VERSION 5.7 ;
  NOWIREEXTENSIONATPIN ON ;
  DIVIDERCHAR "/" ;
  BUSBITCHARS "[]" ;
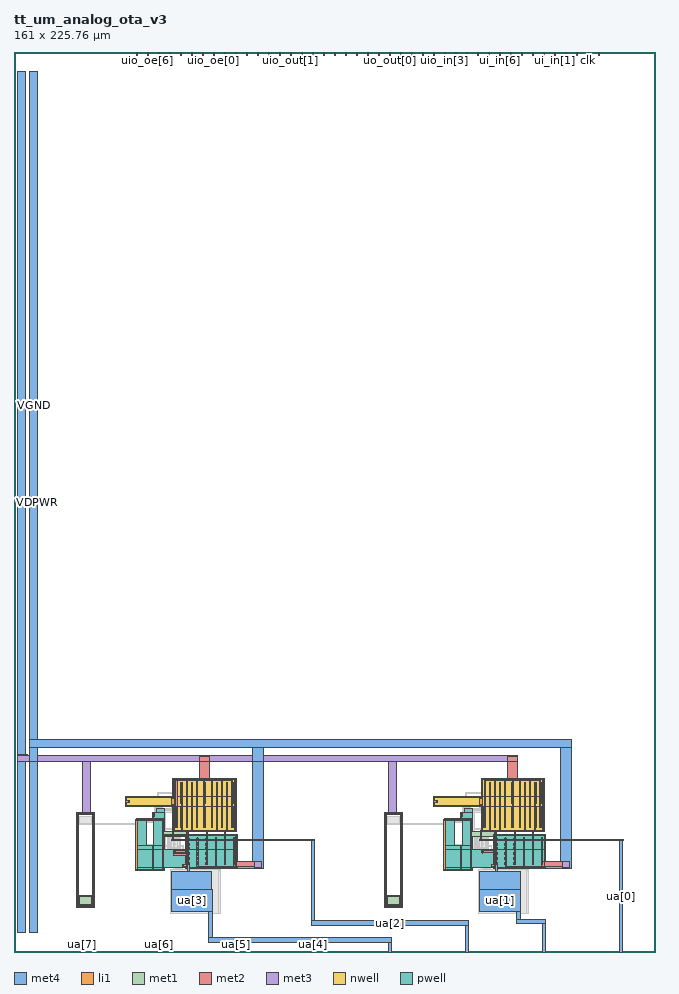
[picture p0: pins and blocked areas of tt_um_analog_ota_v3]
MACRO tt_um_analog_ota_v3
  CLASS BLOCK ;
  FOREIGN tt_um_analog_ota_v3 ;
  ORIGIN 0.000 0.000 ;
  SIZE 161.000 BY 225.760 ;
  PIN clk
    PORT
      LAYER met4 ;
        RECT 143.830 224.760 144.130 225.760 ;
    END
  END clk
  PIN ena
    PORT
      LAYER met4 ;
        RECT 146.590 224.760 146.890 225.760 ;
    END
  END ena
  PIN rst_n
    PORT
      LAYER met4 ;
        RECT 141.070 224.760 141.370 225.760 ;
    END
  END rst_n
  PIN ua[0]
    ANTENNAGATEAREA 0.625000 ;
    PORT
      LAYER li1 ;
        RECT 117.640 28.055 118.140 28.225 ;
      LAYER met1 ;
        RECT 117.715 28.255 118.075 28.270 ;
        RECT 117.660 28.025 118.120 28.255 ;
        RECT 117.715 28.010 118.075 28.025 ;
      LAYER met2 ;
        RECT 117.765 27.950 118.045 28.330 ;
      LAYER met3 ;
        RECT 117.715 27.975 152.770 28.305 ;
        RECT 151.760 27.970 152.770 27.975 ;
      LAYER met4 ;
        RECT 151.805 27.965 152.725 28.310 ;
        RECT 151.810 0.000 152.710 27.965 ;
    END
  END ua[0]
  PIN ua[1]
    ANTENNAGATEAREA 0.625000 ;
    ANTENNADIFFAREA 15.688999 ;
    PORT
      LAYER li1 ;
        RECT 119.250 37.155 119.420 42.495 ;
        RECT 121.830 37.155 122.000 42.495 ;
        RECT 128.110 37.155 128.280 42.495 ;
        RECT 130.690 37.155 130.860 42.495 ;
        RECT 119.250 31.215 119.420 36.555 ;
        RECT 121.830 31.215 122.000 36.555 ;
        RECT 128.110 31.215 128.280 36.555 ;
        RECT 130.690 31.215 130.860 36.555 ;
        RECT 116.850 28.055 117.350 28.225 ;
        RECT 120.935 27.925 121.105 28.615 ;
        RECT 125.515 27.925 125.685 28.615 ;
        RECT 130.095 27.925 130.265 28.615 ;
        RECT 120.935 26.725 121.105 27.415 ;
        RECT 125.515 26.725 125.685 27.415 ;
        RECT 130.095 26.725 130.265 27.415 ;
        RECT 120.935 25.525 121.105 26.215 ;
        RECT 125.515 25.525 125.685 26.215 ;
        RECT 130.095 25.525 130.265 26.215 ;
        RECT 120.935 24.325 121.105 25.015 ;
        RECT 125.515 24.325 125.685 25.015 ;
        RECT 130.095 24.325 130.265 25.015 ;
        RECT 120.935 23.125 121.105 23.815 ;
        RECT 125.515 23.125 125.685 23.815 ;
        RECT 130.095 23.125 130.265 23.815 ;
        RECT 120.935 21.925 121.105 22.615 ;
        RECT 125.515 21.925 125.685 22.615 ;
        RECT 130.095 21.925 130.265 22.615 ;
      LAYER met1 ;
        RECT 119.220 42.460 119.450 42.475 ;
        RECT 121.800 42.460 122.030 42.475 ;
        RECT 128.080 42.460 128.310 42.475 ;
        RECT 130.660 42.460 130.890 42.475 ;
        RECT 119.155 37.190 119.515 42.460 ;
        RECT 121.735 37.190 122.095 42.460 ;
        RECT 128.015 37.190 128.375 42.460 ;
        RECT 130.595 37.190 130.955 42.460 ;
        RECT 119.220 37.175 119.450 37.190 ;
        RECT 121.800 37.175 122.030 37.190 ;
        RECT 128.080 37.175 128.310 37.190 ;
        RECT 130.660 37.175 130.890 37.190 ;
        RECT 119.220 36.520 119.450 36.535 ;
        RECT 121.800 36.520 122.030 36.535 ;
        RECT 128.080 36.520 128.310 36.535 ;
        RECT 130.660 36.520 130.890 36.535 ;
        RECT 119.155 31.250 119.515 36.520 ;
        RECT 121.735 31.250 122.095 36.520 ;
        RECT 128.015 31.250 128.375 36.520 ;
        RECT 130.595 31.250 130.955 36.520 ;
        RECT 119.220 31.235 119.450 31.250 ;
        RECT 121.800 31.235 122.030 31.250 ;
        RECT 128.080 31.235 128.310 31.250 ;
        RECT 130.660 31.235 130.890 31.250 ;
        RECT 120.905 28.535 121.135 28.595 ;
        RECT 125.485 28.535 125.715 28.595 ;
        RECT 130.065 28.535 130.295 28.595 ;
        RECT 116.915 28.255 117.275 28.270 ;
        RECT 116.870 28.025 117.330 28.255 ;
        RECT 116.915 28.010 117.275 28.025 ;
        RECT 120.840 28.005 121.200 28.535 ;
        RECT 125.420 28.005 125.780 28.535 ;
        RECT 130.000 28.005 130.360 28.535 ;
        RECT 120.905 27.945 121.135 28.005 ;
        RECT 125.485 27.945 125.715 28.005 ;
        RECT 130.065 27.945 130.295 28.005 ;
        RECT 120.905 27.335 121.135 27.395 ;
        RECT 125.485 27.335 125.715 27.395 ;
        RECT 130.065 27.335 130.295 27.395 ;
        RECT 120.840 26.805 121.200 27.335 ;
        RECT 125.420 26.805 125.780 27.335 ;
        RECT 130.000 26.805 130.360 27.335 ;
        RECT 120.905 26.745 121.135 26.805 ;
        RECT 125.485 26.745 125.715 26.805 ;
        RECT 130.065 26.745 130.295 26.805 ;
        RECT 120.905 26.135 121.135 26.195 ;
        RECT 125.485 26.135 125.715 26.195 ;
        RECT 130.065 26.135 130.295 26.195 ;
        RECT 120.840 25.605 121.200 26.135 ;
        RECT 125.420 25.605 125.780 26.135 ;
        RECT 130.000 25.605 130.360 26.135 ;
        RECT 120.905 25.545 121.135 25.605 ;
        RECT 125.485 25.545 125.715 25.605 ;
        RECT 130.065 25.545 130.295 25.605 ;
        RECT 120.905 24.935 121.135 24.995 ;
        RECT 125.485 24.935 125.715 24.995 ;
        RECT 130.065 24.935 130.295 24.995 ;
        RECT 120.840 24.405 121.200 24.935 ;
        RECT 125.420 24.405 125.780 24.935 ;
        RECT 130.000 24.405 130.360 24.935 ;
        RECT 120.905 24.345 121.135 24.405 ;
        RECT 125.485 24.345 125.715 24.405 ;
        RECT 130.065 24.345 130.295 24.405 ;
        RECT 120.905 23.735 121.135 23.795 ;
        RECT 125.485 23.735 125.715 23.795 ;
        RECT 130.065 23.735 130.295 23.795 ;
        RECT 120.840 23.205 121.200 23.735 ;
        RECT 125.420 23.205 125.780 23.735 ;
        RECT 130.000 23.205 130.360 23.735 ;
        RECT 120.905 23.145 121.135 23.205 ;
        RECT 125.485 23.145 125.715 23.205 ;
        RECT 130.065 23.145 130.295 23.205 ;
        RECT 120.905 22.535 121.135 22.595 ;
        RECT 125.485 22.535 125.715 22.595 ;
        RECT 130.065 22.535 130.295 22.595 ;
        RECT 120.840 22.005 121.200 22.535 ;
        RECT 125.420 22.005 125.780 22.535 ;
        RECT 130.000 22.005 130.360 22.535 ;
        RECT 120.905 21.945 121.135 22.005 ;
        RECT 125.485 21.945 125.715 22.005 ;
        RECT 130.065 21.945 130.295 22.005 ;
      LAYER met2 ;
        RECT 119.205 30.450 119.465 42.510 ;
        RECT 121.785 30.450 122.045 42.510 ;
        RECT 128.065 30.450 128.325 42.510 ;
        RECT 130.645 30.450 130.905 42.510 ;
        RECT 116.965 30.190 130.905 30.450 ;
        RECT 116.965 28.320 117.185 30.190 ;
        RECT 116.965 27.960 117.225 28.320 ;
        RECT 120.890 22.460 121.150 30.190 ;
        RECT 120.880 22.080 121.160 22.460 ;
        RECT 120.890 21.955 121.150 22.080 ;
        RECT 125.470 21.955 125.730 30.190 ;
        RECT 130.050 21.955 130.310 30.190 ;
      LAYER met3 ;
        RECT 120.770 22.020 121.270 22.520 ;
      LAYER met4 ;
        RECT 120.855 22.105 121.185 22.435 ;
        RECT 120.860 20.175 121.180 22.105 ;
        RECT 116.835 15.780 126.945 20.175 ;
        RECT 116.835 10.065 127.015 15.780 ;
        RECT 126.115 8.255 127.015 10.065 ;
        RECT 126.115 7.030 133.390 8.255 ;
        RECT 132.490 0.000 133.390 7.030 ;
    END
  END ua[1]
  PIN ua[2]
    ANTENNAGATEAREA 0.625000 ;
    PORT
      LAYER li1 ;
        RECT 40.360 28.055 40.860 28.225 ;
      LAYER met1 ;
        RECT 40.435 28.255 40.795 28.270 ;
        RECT 40.380 28.025 40.840 28.255 ;
        RECT 40.435 28.010 40.795 28.025 ;
      LAYER met2 ;
        RECT 40.485 27.950 40.765 28.330 ;
      LAYER met3 ;
        RECT 40.435 27.975 75.490 28.305 ;
        RECT 74.480 27.970 75.490 27.975 ;
      LAYER met4 ;
        RECT 74.525 27.965 75.445 28.310 ;
        RECT 74.530 7.815 75.430 27.965 ;
        RECT 74.530 6.695 114.070 7.815 ;
        RECT 113.170 0.000 114.070 6.695 ;
    END
  END ua[2]
  PIN ua[3]
    ANTENNAGATEAREA 0.625000 ;
    ANTENNADIFFAREA 15.688999 ;
    PORT
      LAYER li1 ;
        RECT 41.970 37.155 42.140 42.495 ;
        RECT 44.550 37.155 44.720 42.495 ;
        RECT 50.830 37.155 51.000 42.495 ;
        RECT 53.410 37.155 53.580 42.495 ;
        RECT 41.970 31.215 42.140 36.555 ;
        RECT 44.550 31.215 44.720 36.555 ;
        RECT 50.830 31.215 51.000 36.555 ;
        RECT 53.410 31.215 53.580 36.555 ;
        RECT 39.570 28.055 40.070 28.225 ;
        RECT 43.655 27.925 43.825 28.615 ;
        RECT 48.235 27.925 48.405 28.615 ;
        RECT 52.815 27.925 52.985 28.615 ;
        RECT 43.655 26.725 43.825 27.415 ;
        RECT 48.235 26.725 48.405 27.415 ;
        RECT 52.815 26.725 52.985 27.415 ;
        RECT 43.655 25.525 43.825 26.215 ;
        RECT 48.235 25.525 48.405 26.215 ;
        RECT 52.815 25.525 52.985 26.215 ;
        RECT 43.655 24.325 43.825 25.015 ;
        RECT 48.235 24.325 48.405 25.015 ;
        RECT 52.815 24.325 52.985 25.015 ;
        RECT 43.655 23.125 43.825 23.815 ;
        RECT 48.235 23.125 48.405 23.815 ;
        RECT 52.815 23.125 52.985 23.815 ;
        RECT 43.655 21.925 43.825 22.615 ;
        RECT 48.235 21.925 48.405 22.615 ;
        RECT 52.815 21.925 52.985 22.615 ;
      LAYER met1 ;
        RECT 41.940 42.460 42.170 42.475 ;
        RECT 44.520 42.460 44.750 42.475 ;
        RECT 50.800 42.460 51.030 42.475 ;
        RECT 53.380 42.460 53.610 42.475 ;
        RECT 41.875 37.190 42.235 42.460 ;
        RECT 44.455 37.190 44.815 42.460 ;
        RECT 50.735 37.190 51.095 42.460 ;
        RECT 53.315 37.190 53.675 42.460 ;
        RECT 41.940 37.175 42.170 37.190 ;
        RECT 44.520 37.175 44.750 37.190 ;
        RECT 50.800 37.175 51.030 37.190 ;
        RECT 53.380 37.175 53.610 37.190 ;
        RECT 41.940 36.520 42.170 36.535 ;
        RECT 44.520 36.520 44.750 36.535 ;
        RECT 50.800 36.520 51.030 36.535 ;
        RECT 53.380 36.520 53.610 36.535 ;
        RECT 41.875 31.250 42.235 36.520 ;
        RECT 44.455 31.250 44.815 36.520 ;
        RECT 50.735 31.250 51.095 36.520 ;
        RECT 53.315 31.250 53.675 36.520 ;
        RECT 41.940 31.235 42.170 31.250 ;
        RECT 44.520 31.235 44.750 31.250 ;
        RECT 50.800 31.235 51.030 31.250 ;
        RECT 53.380 31.235 53.610 31.250 ;
        RECT 43.625 28.535 43.855 28.595 ;
        RECT 48.205 28.535 48.435 28.595 ;
        RECT 52.785 28.535 53.015 28.595 ;
        RECT 39.635 28.255 39.995 28.270 ;
        RECT 39.590 28.025 40.050 28.255 ;
        RECT 39.635 28.010 39.995 28.025 ;
        RECT 43.560 28.005 43.920 28.535 ;
        RECT 48.140 28.005 48.500 28.535 ;
        RECT 52.720 28.005 53.080 28.535 ;
        RECT 43.625 27.945 43.855 28.005 ;
        RECT 48.205 27.945 48.435 28.005 ;
        RECT 52.785 27.945 53.015 28.005 ;
        RECT 43.625 27.335 43.855 27.395 ;
        RECT 48.205 27.335 48.435 27.395 ;
        RECT 52.785 27.335 53.015 27.395 ;
        RECT 43.560 26.805 43.920 27.335 ;
        RECT 48.140 26.805 48.500 27.335 ;
        RECT 52.720 26.805 53.080 27.335 ;
        RECT 43.625 26.745 43.855 26.805 ;
        RECT 48.205 26.745 48.435 26.805 ;
        RECT 52.785 26.745 53.015 26.805 ;
        RECT 43.625 26.135 43.855 26.195 ;
        RECT 48.205 26.135 48.435 26.195 ;
        RECT 52.785 26.135 53.015 26.195 ;
        RECT 43.560 25.605 43.920 26.135 ;
        RECT 48.140 25.605 48.500 26.135 ;
        RECT 52.720 25.605 53.080 26.135 ;
        RECT 43.625 25.545 43.855 25.605 ;
        RECT 48.205 25.545 48.435 25.605 ;
        RECT 52.785 25.545 53.015 25.605 ;
        RECT 43.625 24.935 43.855 24.995 ;
        RECT 48.205 24.935 48.435 24.995 ;
        RECT 52.785 24.935 53.015 24.995 ;
        RECT 43.560 24.405 43.920 24.935 ;
        RECT 48.140 24.405 48.500 24.935 ;
        RECT 52.720 24.405 53.080 24.935 ;
        RECT 43.625 24.345 43.855 24.405 ;
        RECT 48.205 24.345 48.435 24.405 ;
        RECT 52.785 24.345 53.015 24.405 ;
        RECT 43.625 23.735 43.855 23.795 ;
        RECT 48.205 23.735 48.435 23.795 ;
        RECT 52.785 23.735 53.015 23.795 ;
        RECT 43.560 23.205 43.920 23.735 ;
        RECT 48.140 23.205 48.500 23.735 ;
        RECT 52.720 23.205 53.080 23.735 ;
        RECT 43.625 23.145 43.855 23.205 ;
        RECT 48.205 23.145 48.435 23.205 ;
        RECT 52.785 23.145 53.015 23.205 ;
        RECT 43.625 22.535 43.855 22.595 ;
        RECT 48.205 22.535 48.435 22.595 ;
        RECT 52.785 22.535 53.015 22.595 ;
        RECT 43.560 22.005 43.920 22.535 ;
        RECT 48.140 22.005 48.500 22.535 ;
        RECT 52.720 22.005 53.080 22.535 ;
        RECT 43.625 21.945 43.855 22.005 ;
        RECT 48.205 21.945 48.435 22.005 ;
        RECT 52.785 21.945 53.015 22.005 ;
      LAYER met2 ;
        RECT 41.925 30.450 42.185 42.510 ;
        RECT 44.505 30.450 44.765 42.510 ;
        RECT 50.785 30.450 51.045 42.510 ;
        RECT 53.365 30.450 53.625 42.510 ;
        RECT 39.685 30.190 53.625 30.450 ;
        RECT 39.685 28.320 39.905 30.190 ;
        RECT 39.685 27.960 39.945 28.320 ;
        RECT 43.610 22.460 43.870 30.190 ;
        RECT 43.600 22.080 43.880 22.460 ;
        RECT 43.610 21.955 43.870 22.080 ;
        RECT 48.190 21.955 48.450 30.190 ;
        RECT 52.770 21.955 53.030 30.190 ;
      LAYER met3 ;
        RECT 43.490 22.020 43.990 22.520 ;
      LAYER met4 ;
        RECT 43.575 22.105 43.905 22.435 ;
        RECT 43.580 20.175 43.900 22.105 ;
        RECT 39.555 15.780 49.665 20.175 ;
        RECT 39.555 10.065 49.735 15.780 ;
        RECT 48.835 3.660 49.735 10.065 ;
        RECT 48.835 3.565 55.210 3.660 ;
        RECT 48.835 3.555 56.965 3.565 ;
        RECT 48.835 2.435 94.750 3.555 ;
        RECT 93.850 0.000 94.750 2.435 ;
    END
  END ua[3]
  PIN ua[4]
    PORT
      LAYER met4 ;
        RECT 74.530 0.000 75.430 1.000 ;
    END
  END ua[4]
  PIN ua[5]
    PORT
      LAYER met4 ;
        RECT 55.210 0.000 56.110 1.000 ;
    END
  END ua[5]
  PIN ua[6]
    PORT
      LAYER met4 ;
        RECT 35.890 0.000 36.790 1.000 ;
    END
  END ua[6]
  PIN ua[7]
    PORT
      LAYER met4 ;
        RECT 16.570 0.000 17.470 1.000 ;
    END
  END ua[7]
  PIN ui_in[0]
    PORT
      LAYER met4 ;
        RECT 138.310 224.760 138.610 225.760 ;
    END
  END ui_in[0]
  PIN ui_in[1]
    PORT
      LAYER met4 ;
        RECT 135.550 224.760 135.850 225.760 ;
    END
  END ui_in[1]
  PIN ui_in[2]
    PORT
      LAYER met4 ;
        RECT 132.790 224.760 133.090 225.760 ;
    END
  END ui_in[2]
  PIN ui_in[3]
    PORT
      LAYER met4 ;
        RECT 130.030 224.760 130.330 225.760 ;
    END
  END ui_in[3]
  PIN ui_in[4]
    PORT
      LAYER met4 ;
        RECT 127.270 224.760 127.570 225.760 ;
    END
  END ui_in[4]
  PIN ui_in[5]
    PORT
      LAYER met4 ;
        RECT 124.510 224.760 124.810 225.760 ;
    END
  END ui_in[5]
  PIN ui_in[6]
    PORT
      LAYER met4 ;
        RECT 121.750 224.760 122.050 225.760 ;
    END
  END ui_in[6]
  PIN ui_in[7]
    PORT
      LAYER met4 ;
        RECT 118.990 224.760 119.290 225.760 ;
    END
  END ui_in[7]
  PIN uio_in[0]
    PORT
      LAYER met4 ;
        RECT 116.230 224.760 116.530 225.760 ;
    END
  END uio_in[0]
  PIN uio_in[1]
    PORT
      LAYER met4 ;
        RECT 113.470 224.760 113.770 225.760 ;
    END
  END uio_in[1]
  PIN uio_in[2]
    PORT
      LAYER met4 ;
        RECT 110.710 224.760 111.010 225.760 ;
    END
  END uio_in[2]
  PIN uio_in[3]
    PORT
      LAYER met4 ;
        RECT 107.950 224.760 108.250 225.760 ;
    END
  END uio_in[3]
  PIN uio_in[4]
    PORT
      LAYER met4 ;
        RECT 105.190 224.760 105.490 225.760 ;
    END
  END uio_in[4]
  PIN uio_in[5]
    PORT
      LAYER met4 ;
        RECT 102.430 224.760 102.730 225.760 ;
    END
  END uio_in[5]
  PIN uio_in[6]
    PORT
      LAYER met4 ;
        RECT 99.670 224.760 99.970 225.760 ;
    END
  END uio_in[6]
  PIN uio_in[7]
    PORT
      LAYER met4 ;
        RECT 96.910 224.760 97.210 225.760 ;
    END
  END uio_in[7]
  PIN uio_oe[0]
    PORT
      LAYER met4 ;
        RECT 49.990 224.760 50.290 225.760 ;
    END
  END uio_oe[0]
  PIN uio_oe[1]
    PORT
      LAYER met4 ;
        RECT 47.230 224.760 47.530 225.760 ;
    END
  END uio_oe[1]
  PIN uio_oe[2]
    PORT
      LAYER met4 ;
        RECT 44.470 224.760 44.770 225.760 ;
    END
  END uio_oe[2]
  PIN uio_oe[3]
    PORT
      LAYER met4 ;
        RECT 41.710 224.760 42.010 225.760 ;
    END
  END uio_oe[3]
  PIN uio_oe[4]
    PORT
      LAYER met4 ;
        RECT 38.950 224.760 39.250 225.760 ;
    END
  END uio_oe[4]
  PIN uio_oe[5]
    PORT
      LAYER met4 ;
        RECT 36.190 224.760 36.490 225.760 ;
    END
  END uio_oe[5]
  PIN uio_oe[6]
    PORT
      LAYER met4 ;
        RECT 33.430 224.760 33.730 225.760 ;
    END
  END uio_oe[6]
  PIN uio_oe[7]
    PORT
      LAYER met4 ;
        RECT 30.670 224.760 30.970 225.760 ;
    END
  END uio_oe[7]
  PIN uio_out[0]
    PORT
      LAYER met4 ;
        RECT 72.070 224.760 72.370 225.760 ;
    END
  END uio_out[0]
  PIN uio_out[1]
    PORT
      LAYER met4 ;
        RECT 69.310 224.760 69.610 225.760 ;
    END
  END uio_out[1]
  PIN uio_out[2]
    PORT
      LAYER met4 ;
        RECT 66.550 224.760 66.850 225.760 ;
    END
  END uio_out[2]
  PIN uio_out[3]
    PORT
      LAYER met4 ;
        RECT 63.790 224.760 64.090 225.760 ;
    END
  END uio_out[3]
  PIN uio_out[4]
    PORT
      LAYER met4 ;
        RECT 61.030 224.760 61.330 225.760 ;
    END
  END uio_out[4]
  PIN uio_out[5]
    PORT
      LAYER met4 ;
        RECT 58.270 224.760 58.570 225.760 ;
    END
  END uio_out[5]
  PIN uio_out[6]
    PORT
      LAYER met4 ;
        RECT 55.510 224.760 55.810 225.760 ;
    END
  END uio_out[6]
  PIN uio_out[7]
    PORT
      LAYER met4 ;
        RECT 52.750 224.760 53.050 225.760 ;
    END
  END uio_out[7]
  PIN uo_out[0]
    PORT
      LAYER met4 ;
        RECT 94.150 224.760 94.450 225.760 ;
    END
  END uo_out[0]
  PIN uo_out[1]
    PORT
      LAYER met4 ;
        RECT 91.390 224.760 91.690 225.760 ;
    END
  END uo_out[1]
  PIN uo_out[2]
    PORT
      LAYER met4 ;
        RECT 88.630 224.760 88.930 225.760 ;
    END
  END uo_out[2]
  PIN uo_out[3]
    PORT
      LAYER met4 ;
        RECT 85.870 224.760 86.170 225.760 ;
    END
  END uo_out[3]
  PIN uo_out[4]
    PORT
      LAYER met4 ;
        RECT 83.110 224.760 83.410 225.760 ;
    END
  END uo_out[4]
  PIN uo_out[5]
    PORT
      LAYER met4 ;
        RECT 80.350 224.760 80.650 225.760 ;
    END
  END uo_out[5]
  PIN uo_out[6]
    PORT
      LAYER met4 ;
        RECT 77.590 224.760 77.890 225.760 ;
    END
  END uo_out[6]
  PIN uo_out[7]
    PORT
      LAYER met4 ;
        RECT 74.830 224.760 75.130 225.760 ;
    END
  END uo_out[7]
  PIN VDPWR
    ANTENNADIFFAREA 87.219597 ;
    PORT
      LAYER nwell ;
        RECT 39.865 39.080 55.695 43.570 ;
        RECT 117.145 39.080 132.975 43.570 ;
        RECT 27.875 36.450 55.695 39.080 ;
        RECT 105.155 36.450 132.975 39.080 ;
      LAYER pwell ;
        RECT 15.710 34.445 20.120 34.875 ;
        RECT 15.710 11.585 16.140 34.445 ;
        RECT 19.690 11.585 20.120 34.445 ;
      LAYER nwell ;
        RECT 39.865 30.190 55.695 36.450 ;
      LAYER pwell ;
        RECT 92.990 34.445 97.400 34.875 ;
        RECT 15.710 11.155 20.120 11.585 ;
        RECT 92.990 11.585 93.420 34.445 ;
        RECT 96.970 11.585 97.400 34.445 ;
      LAYER nwell ;
        RECT 117.145 30.190 132.975 36.450 ;
      LAYER pwell ;
        RECT 92.990 11.155 97.400 11.585 ;
      LAYER li1 ;
        RECT 40.045 43.220 55.515 43.390 ;
        RECT 28.055 38.730 39.775 38.900 ;
        RECT 28.055 38.035 28.225 38.730 ;
        RECT 39.605 38.600 39.775 38.730 ;
        RECT 40.045 38.600 40.215 43.220 ;
        RECT 28.055 37.495 28.850 38.035 ;
        RECT 28.055 36.800 28.225 37.495 ;
        RECT 39.605 36.930 40.215 38.600 ;
        RECT 43.260 37.155 43.430 42.495 ;
        RECT 45.840 37.155 46.010 42.495 ;
        RECT 47.690 37.155 47.860 42.495 ;
        RECT 49.540 37.155 49.710 42.495 ;
        RECT 52.120 37.155 52.290 42.495 ;
        RECT 54.700 37.155 54.870 42.495 ;
        RECT 39.605 36.800 39.775 36.930 ;
        RECT 28.055 36.630 39.775 36.800 ;
        RECT 15.840 34.575 19.990 34.745 ;
        RECT 15.840 11.455 16.010 34.575 ;
        RECT 16.490 11.455 19.340 14.095 ;
        RECT 19.820 11.455 19.990 34.575 ;
        RECT 40.045 30.540 40.215 36.930 ;
        RECT 40.680 31.215 40.850 36.555 ;
        RECT 43.260 31.215 43.430 36.555 ;
        RECT 45.840 31.215 46.010 36.555 ;
        RECT 47.690 31.215 47.860 36.555 ;
        RECT 49.540 31.215 49.710 36.555 ;
        RECT 52.120 31.215 52.290 36.555 ;
        RECT 54.700 31.215 54.870 36.555 ;
        RECT 55.345 30.540 55.515 43.220 ;
        RECT 117.325 43.220 132.795 43.390 ;
        RECT 105.335 38.730 117.055 38.900 ;
        RECT 105.335 38.035 105.505 38.730 ;
        RECT 116.885 38.600 117.055 38.730 ;
        RECT 117.325 38.600 117.495 43.220 ;
        RECT 105.335 37.495 106.130 38.035 ;
        RECT 105.335 36.800 105.505 37.495 ;
        RECT 116.885 36.930 117.495 38.600 ;
        RECT 120.540 37.155 120.710 42.495 ;
        RECT 123.120 37.155 123.290 42.495 ;
        RECT 124.970 37.155 125.140 42.495 ;
        RECT 126.820 37.155 126.990 42.495 ;
        RECT 129.400 37.155 129.570 42.495 ;
        RECT 131.980 37.155 132.150 42.495 ;
        RECT 116.885 36.800 117.055 36.930 ;
        RECT 105.335 36.630 117.055 36.800 ;
        RECT 40.045 30.370 55.515 30.540 ;
        RECT 93.120 34.575 97.270 34.745 ;
        RECT 15.840 11.285 19.990 11.455 ;
        RECT 93.120 11.455 93.290 34.575 ;
        RECT 93.770 11.455 96.620 14.095 ;
        RECT 97.100 11.455 97.270 34.575 ;
        RECT 117.325 30.540 117.495 36.930 ;
        RECT 117.960 31.215 118.130 36.555 ;
        RECT 120.540 31.215 120.710 36.555 ;
        RECT 123.120 31.215 123.290 36.555 ;
        RECT 124.970 31.215 125.140 36.555 ;
        RECT 126.820 31.215 126.990 36.555 ;
        RECT 129.400 31.215 129.570 36.555 ;
        RECT 131.980 31.215 132.150 36.555 ;
        RECT 132.625 30.540 132.795 43.220 ;
        RECT 117.325 30.370 132.795 30.540 ;
        RECT 93.120 11.285 97.270 11.455 ;
      LAYER met1 ;
        RECT 40.585 43.420 54.965 43.435 ;
        RECT 117.865 43.420 132.245 43.435 ;
        RECT 40.575 43.190 54.975 43.420 ;
        RECT 117.855 43.190 132.255 43.420 ;
        RECT 40.585 43.175 54.965 43.190 ;
        RECT 117.865 43.175 132.245 43.190 ;
        RECT 43.230 42.460 43.460 42.475 ;
        RECT 45.810 42.460 46.040 42.475 ;
        RECT 47.660 42.460 47.890 42.475 ;
        RECT 49.510 42.460 49.740 42.475 ;
        RECT 52.090 42.460 52.320 42.475 ;
        RECT 54.670 42.460 54.900 42.475 ;
        RECT 120.510 42.460 120.740 42.475 ;
        RECT 123.090 42.460 123.320 42.475 ;
        RECT 124.940 42.460 125.170 42.475 ;
        RECT 126.790 42.460 127.020 42.475 ;
        RECT 129.370 42.460 129.600 42.475 ;
        RECT 131.950 42.460 132.180 42.475 ;
        RECT 28.650 37.515 28.880 38.015 ;
        RECT 43.165 37.190 43.525 42.460 ;
        RECT 45.745 37.190 46.105 42.460 ;
        RECT 47.595 37.190 47.955 42.460 ;
        RECT 49.445 37.190 49.805 42.460 ;
        RECT 52.025 37.190 52.385 42.460 ;
        RECT 54.605 37.190 54.965 42.460 ;
        RECT 105.930 37.515 106.160 38.015 ;
        RECT 120.445 37.190 120.805 42.460 ;
        RECT 123.025 37.190 123.385 42.460 ;
        RECT 124.875 37.190 125.235 42.460 ;
        RECT 126.725 37.190 127.085 42.460 ;
        RECT 129.305 37.190 129.665 42.460 ;
        RECT 131.885 37.190 132.245 42.460 ;
        RECT 43.230 37.175 43.460 37.190 ;
        RECT 45.810 37.175 46.040 37.190 ;
        RECT 47.660 37.175 47.890 37.190 ;
        RECT 49.510 37.175 49.740 37.190 ;
        RECT 52.090 37.175 52.320 37.190 ;
        RECT 54.670 37.175 54.900 37.190 ;
        RECT 120.510 37.175 120.740 37.190 ;
        RECT 123.090 37.175 123.320 37.190 ;
        RECT 124.940 37.175 125.170 37.190 ;
        RECT 126.790 37.175 127.020 37.190 ;
        RECT 129.370 37.175 129.600 37.190 ;
        RECT 131.950 37.175 132.180 37.190 ;
        RECT 40.650 36.520 40.880 36.535 ;
        RECT 43.230 36.520 43.460 36.535 ;
        RECT 45.810 36.520 46.040 36.535 ;
        RECT 47.660 36.520 47.890 36.535 ;
        RECT 49.510 36.520 49.740 36.535 ;
        RECT 52.090 36.520 52.320 36.535 ;
        RECT 54.670 36.520 54.900 36.535 ;
        RECT 117.930 36.520 118.160 36.535 ;
        RECT 120.510 36.520 120.740 36.535 ;
        RECT 123.090 36.520 123.320 36.535 ;
        RECT 124.940 36.520 125.170 36.535 ;
        RECT 126.790 36.520 127.020 36.535 ;
        RECT 129.370 36.520 129.600 36.535 ;
        RECT 131.950 36.520 132.180 36.535 ;
        RECT 17.170 34.775 19.100 34.950 ;
        RECT 17.150 34.545 19.100 34.775 ;
        RECT 17.170 34.495 19.100 34.545 ;
        RECT 40.585 31.250 40.945 36.520 ;
        RECT 43.165 31.250 43.525 36.520 ;
        RECT 45.745 31.250 46.105 36.520 ;
        RECT 47.595 31.250 47.955 36.520 ;
        RECT 49.445 31.250 49.805 36.520 ;
        RECT 52.025 31.250 52.385 36.520 ;
        RECT 54.605 31.250 54.965 36.520 ;
        RECT 93.905 34.775 95.880 34.840 ;
        RECT 93.905 34.545 95.885 34.775 ;
        RECT 93.905 34.520 95.880 34.545 ;
        RECT 117.865 31.250 118.225 36.520 ;
        RECT 120.445 31.250 120.805 36.520 ;
        RECT 123.025 31.250 123.385 36.520 ;
        RECT 124.875 31.250 125.235 36.520 ;
        RECT 126.725 31.250 127.085 36.520 ;
        RECT 129.305 31.250 129.665 36.520 ;
        RECT 131.885 31.250 132.245 36.520 ;
        RECT 40.650 31.235 40.880 31.250 ;
        RECT 43.230 31.235 43.460 31.250 ;
        RECT 45.810 31.235 46.040 31.250 ;
        RECT 47.660 31.235 47.890 31.250 ;
        RECT 49.510 31.235 49.740 31.250 ;
        RECT 52.090 31.235 52.320 31.250 ;
        RECT 54.670 31.235 54.900 31.250 ;
        RECT 117.930 31.235 118.160 31.250 ;
        RECT 120.510 31.235 120.740 31.250 ;
        RECT 123.090 31.235 123.320 31.250 ;
        RECT 124.940 31.235 125.170 31.250 ;
        RECT 126.790 31.235 127.020 31.250 ;
        RECT 129.370 31.235 129.600 31.250 ;
        RECT 131.950 31.235 132.180 31.250 ;
        RECT 16.510 11.995 19.320 14.040 ;
        RECT 93.790 11.995 96.600 14.040 ;
      LAYER met2 ;
        RECT 46.505 43.485 48.960 49.105 ;
        RECT 123.785 43.485 126.240 49.105 ;
        RECT 40.635 43.125 54.915 43.485 ;
        RECT 17.220 34.445 19.050 35.000 ;
        RECT 40.635 31.200 40.895 43.125 ;
        RECT 43.215 31.200 43.475 43.125 ;
        RECT 45.795 31.200 46.055 43.125 ;
        RECT 47.645 31.200 47.905 43.125 ;
        RECT 49.495 31.200 49.755 43.125 ;
        RECT 52.075 31.200 52.335 43.125 ;
        RECT 54.655 31.200 54.915 43.125 ;
        RECT 117.915 43.125 132.195 43.485 ;
        RECT 93.955 34.470 95.830 34.890 ;
        RECT 117.915 31.200 118.175 43.125 ;
        RECT 120.495 31.200 120.755 43.125 ;
        RECT 123.075 31.200 123.335 43.125 ;
        RECT 124.925 31.200 125.185 43.125 ;
        RECT 126.775 31.200 127.035 43.125 ;
        RECT 129.355 31.200 129.615 43.125 ;
        RECT 131.935 31.200 132.195 43.125 ;
      LAYER met3 ;
        RECT 0.975 49.460 2.955 49.480 ;
        RECT 0.975 49.350 3.335 49.460 ;
        RECT 0.975 47.725 126.345 49.350 ;
        RECT 2.935 47.720 126.345 47.725 ;
        RECT 17.195 34.975 19.065 47.720 ;
        RECT 17.170 34.470 19.100 34.975 ;
        RECT 93.965 34.865 95.835 47.720 ;
        RECT 93.905 34.495 95.880 34.865 ;
      LAYER met4 ;
        RECT 1.000 5.000 3.000 220.760 ;
    END
  END VDPWR
  PIN VGND
    USE GROUND ;
    PORT
      LAYER pwell ;
        RECT 35.800 35.080 37.640 36.080 ;
        RECT 113.080 35.080 114.920 36.080 ;
        RECT 34.745 33.485 37.640 35.080 ;
        RECT 112.025 33.485 114.920 35.080 ;
        RECT 30.680 33.055 37.640 33.485 ;
        RECT 30.680 26.795 33.240 33.055 ;
        RECT 35.100 26.795 37.640 33.055 ;
        RECT 107.960 33.055 114.920 33.485 ;
        RECT 30.680 25.620 37.640 26.795 ;
        RECT 42.955 25.620 55.975 29.595 ;
        RECT 30.680 21.230 55.975 25.620 ;
        RECT 30.680 20.375 37.640 21.230 ;
        RECT 42.955 20.945 55.975 21.230 ;
        RECT 107.960 26.795 110.520 33.055 ;
        RECT 112.380 26.795 114.920 33.055 ;
        RECT 107.960 25.620 114.920 26.795 ;
        RECT 120.235 25.620 133.255 29.595 ;
        RECT 107.960 21.230 133.255 25.620 ;
        RECT 107.960 20.375 114.920 21.230 ;
        RECT 120.235 20.945 133.255 21.230 ;
      LAYER li1 ;
        RECT 34.935 34.160 35.105 34.970 ;
        RECT 112.215 34.160 112.385 34.970 ;
        RECT 34.660 33.930 35.105 34.160 ;
        RECT 111.940 33.930 112.385 34.160 ;
        RECT 34.660 33.355 34.890 33.930 ;
        RECT 111.940 33.355 112.170 33.930 ;
        RECT 30.540 33.185 37.510 33.355 ;
        RECT 30.540 20.675 30.980 33.185 ;
        RECT 34.730 20.675 34.900 26.685 ;
        RECT 37.340 20.675 37.510 33.185 ;
        RECT 107.820 33.185 114.790 33.355 ;
        RECT 43.085 29.295 55.845 29.465 ;
        RECT 40.130 24.820 40.300 25.510 ;
        RECT 43.085 22.030 43.255 29.295 ;
        RECT 45.945 27.925 46.115 28.615 ;
        RECT 50.525 27.925 50.695 28.615 ;
        RECT 55.105 27.925 55.275 28.615 ;
        RECT 45.945 26.725 46.115 27.415 ;
        RECT 50.525 26.725 50.695 27.415 ;
        RECT 55.105 26.725 55.275 27.415 ;
        RECT 45.945 25.525 46.115 26.215 ;
        RECT 50.525 25.525 50.695 26.215 ;
        RECT 55.105 25.525 55.275 26.215 ;
        RECT 45.945 24.325 46.115 25.015 ;
        RECT 50.525 24.325 50.695 25.015 ;
        RECT 55.105 24.325 55.275 25.015 ;
        RECT 45.945 23.125 46.115 23.815 ;
        RECT 50.525 23.125 50.695 23.815 ;
        RECT 55.105 23.125 55.275 23.815 ;
        RECT 42.420 21.340 43.255 22.030 ;
        RECT 45.945 21.925 46.115 22.615 ;
        RECT 50.525 21.925 50.695 22.615 ;
        RECT 55.105 21.925 55.275 22.615 ;
        RECT 43.085 21.245 43.255 21.340 ;
        RECT 55.675 21.245 55.845 29.295 ;
        RECT 43.085 21.075 55.845 21.245 ;
        RECT 30.540 20.505 37.510 20.675 ;
        RECT 107.820 20.675 108.260 33.185 ;
        RECT 112.010 20.675 112.180 26.685 ;
        RECT 114.620 20.675 114.790 33.185 ;
        RECT 120.365 29.295 133.125 29.465 ;
        RECT 117.410 24.820 117.580 25.510 ;
        RECT 120.365 22.030 120.535 29.295 ;
        RECT 123.225 27.925 123.395 28.615 ;
        RECT 127.805 27.925 127.975 28.615 ;
        RECT 132.385 27.925 132.555 28.615 ;
        RECT 123.225 26.725 123.395 27.415 ;
        RECT 127.805 26.725 127.975 27.415 ;
        RECT 132.385 26.725 132.555 27.415 ;
        RECT 123.225 25.525 123.395 26.215 ;
        RECT 127.805 25.525 127.975 26.215 ;
        RECT 132.385 25.525 132.555 26.215 ;
        RECT 123.225 24.325 123.395 25.015 ;
        RECT 127.805 24.325 127.975 25.015 ;
        RECT 132.385 24.325 132.555 25.015 ;
        RECT 123.225 23.125 123.395 23.815 ;
        RECT 127.805 23.125 127.975 23.815 ;
        RECT 132.385 23.125 132.555 23.815 ;
        RECT 119.700 21.340 120.535 22.030 ;
        RECT 123.225 21.925 123.395 22.615 ;
        RECT 127.805 21.925 127.975 22.615 ;
        RECT 132.385 21.925 132.555 22.615 ;
        RECT 120.365 21.245 120.535 21.340 ;
        RECT 132.955 21.245 133.125 29.295 ;
        RECT 120.365 21.075 133.125 21.245 ;
        RECT 107.820 20.505 114.790 20.675 ;
      LAYER met1 ;
        RECT 34.905 33.950 35.135 34.950 ;
        RECT 112.185 33.950 112.415 34.950 ;
        RECT 37.310 29.495 43.355 30.145 ;
        RECT 37.280 29.265 43.355 29.495 ;
        RECT 37.310 28.925 43.355 29.265 ;
        RECT 114.550 28.925 120.595 30.145 ;
        RECT 45.915 28.535 46.145 28.595 ;
        RECT 50.495 28.535 50.725 28.595 ;
        RECT 55.075 28.535 55.305 28.595 ;
        RECT 123.195 28.535 123.425 28.595 ;
        RECT 127.775 28.535 128.005 28.595 ;
        RECT 132.355 28.535 132.585 28.595 ;
        RECT 45.850 28.005 46.210 28.535 ;
        RECT 50.430 28.005 50.790 28.535 ;
        RECT 55.010 28.005 55.370 28.535 ;
        RECT 123.130 28.005 123.490 28.535 ;
        RECT 127.710 28.005 128.070 28.535 ;
        RECT 132.290 28.005 132.650 28.535 ;
        RECT 45.915 27.945 46.145 28.005 ;
        RECT 50.495 27.945 50.725 28.005 ;
        RECT 55.075 27.945 55.305 28.005 ;
        RECT 123.195 27.945 123.425 28.005 ;
        RECT 127.775 27.945 128.005 28.005 ;
        RECT 132.355 27.945 132.585 28.005 ;
        RECT 45.915 27.335 46.145 27.395 ;
        RECT 50.495 27.335 50.725 27.395 ;
        RECT 55.075 27.335 55.305 27.395 ;
        RECT 123.195 27.335 123.425 27.395 ;
        RECT 127.775 27.335 128.005 27.395 ;
        RECT 132.355 27.335 132.585 27.395 ;
        RECT 45.850 26.805 46.210 27.335 ;
        RECT 50.430 26.805 50.790 27.335 ;
        RECT 55.010 26.805 55.370 27.335 ;
        RECT 123.130 26.805 123.490 27.335 ;
        RECT 127.710 26.805 128.070 27.335 ;
        RECT 132.290 26.805 132.650 27.335 ;
        RECT 45.915 26.745 46.145 26.805 ;
        RECT 50.495 26.745 50.725 26.805 ;
        RECT 55.075 26.745 55.305 26.805 ;
        RECT 123.195 26.745 123.425 26.805 ;
        RECT 127.775 26.745 128.005 26.805 ;
        RECT 132.355 26.745 132.585 26.805 ;
        RECT 34.700 21.665 34.930 26.665 ;
        RECT 45.915 26.135 46.145 26.195 ;
        RECT 50.495 26.135 50.725 26.195 ;
        RECT 55.075 26.135 55.305 26.195 ;
        RECT 45.850 25.605 46.210 26.135 ;
        RECT 50.430 25.605 50.790 26.135 ;
        RECT 55.010 25.605 55.370 26.135 ;
        RECT 45.915 25.545 46.145 25.605 ;
        RECT 50.495 25.545 50.725 25.605 ;
        RECT 55.075 25.545 55.305 25.605 ;
        RECT 40.100 25.430 40.330 25.490 ;
        RECT 43.055 25.430 43.285 25.490 ;
        RECT 40.035 24.900 40.395 25.430 ;
        RECT 42.990 24.900 43.350 25.430 ;
        RECT 45.915 24.935 46.145 24.995 ;
        RECT 50.495 24.935 50.725 24.995 ;
        RECT 55.075 24.935 55.305 24.995 ;
        RECT 40.100 24.840 40.330 24.900 ;
        RECT 43.055 24.840 43.285 24.900 ;
        RECT 45.850 24.405 46.210 24.935 ;
        RECT 50.430 24.405 50.790 24.935 ;
        RECT 55.010 24.405 55.370 24.935 ;
        RECT 45.915 24.345 46.145 24.405 ;
        RECT 50.495 24.345 50.725 24.405 ;
        RECT 55.075 24.345 55.305 24.405 ;
        RECT 45.915 23.735 46.145 23.795 ;
        RECT 50.495 23.735 50.725 23.795 ;
        RECT 55.075 23.735 55.305 23.795 ;
        RECT 45.850 23.205 46.210 23.735 ;
        RECT 50.430 23.205 50.790 23.735 ;
        RECT 55.010 23.205 55.370 23.735 ;
        RECT 45.915 23.145 46.145 23.205 ;
        RECT 50.495 23.145 50.725 23.205 ;
        RECT 55.075 23.145 55.305 23.205 ;
        RECT 45.915 22.535 46.145 22.595 ;
        RECT 50.495 22.535 50.725 22.595 ;
        RECT 55.075 22.535 55.305 22.595 ;
        RECT 42.390 21.360 42.620 22.010 ;
        RECT 45.850 22.005 46.210 22.535 ;
        RECT 50.430 22.005 50.790 22.535 ;
        RECT 55.010 22.005 55.370 22.535 ;
        RECT 45.915 21.945 46.145 22.005 ;
        RECT 50.495 21.945 50.725 22.005 ;
        RECT 55.075 21.945 55.305 22.005 ;
        RECT 111.980 21.665 112.210 26.665 ;
        RECT 123.195 26.135 123.425 26.195 ;
        RECT 127.775 26.135 128.005 26.195 ;
        RECT 132.355 26.135 132.585 26.195 ;
        RECT 123.130 25.605 123.490 26.135 ;
        RECT 127.710 25.605 128.070 26.135 ;
        RECT 132.290 25.605 132.650 26.135 ;
        RECT 123.195 25.545 123.425 25.605 ;
        RECT 127.775 25.545 128.005 25.605 ;
        RECT 132.355 25.545 132.585 25.605 ;
        RECT 117.380 25.430 117.610 25.490 ;
        RECT 120.335 25.430 120.565 25.490 ;
        RECT 117.315 24.900 117.675 25.430 ;
        RECT 120.270 24.900 120.630 25.430 ;
        RECT 123.195 24.935 123.425 24.995 ;
        RECT 127.775 24.935 128.005 24.995 ;
        RECT 132.355 24.935 132.585 24.995 ;
        RECT 117.380 24.840 117.610 24.900 ;
        RECT 120.335 24.840 120.565 24.900 ;
        RECT 123.130 24.405 123.490 24.935 ;
        RECT 127.710 24.405 128.070 24.935 ;
        RECT 132.290 24.405 132.650 24.935 ;
        RECT 123.195 24.345 123.425 24.405 ;
        RECT 127.775 24.345 128.005 24.405 ;
        RECT 132.355 24.345 132.585 24.405 ;
        RECT 123.195 23.735 123.425 23.795 ;
        RECT 127.775 23.735 128.005 23.795 ;
        RECT 132.355 23.735 132.585 23.795 ;
        RECT 123.130 23.205 123.490 23.735 ;
        RECT 127.710 23.205 128.070 23.735 ;
        RECT 132.290 23.205 132.650 23.735 ;
        RECT 123.195 23.145 123.425 23.205 ;
        RECT 127.775 23.145 128.005 23.205 ;
        RECT 132.355 23.145 132.585 23.205 ;
        RECT 123.195 22.535 123.425 22.595 ;
        RECT 127.775 22.535 128.005 22.595 ;
        RECT 132.355 22.535 132.585 22.595 ;
        RECT 119.670 21.360 119.900 22.010 ;
        RECT 123.130 22.005 123.490 22.535 ;
        RECT 127.710 22.005 128.070 22.535 ;
        RECT 132.290 22.005 132.650 22.535 ;
        RECT 123.195 21.945 123.425 22.005 ;
        RECT 127.775 21.945 128.005 22.005 ;
        RECT 132.355 21.945 132.585 22.005 ;
        RECT 45.840 21.275 55.415 21.290 ;
        RECT 123.120 21.275 132.695 21.290 ;
        RECT 45.840 21.045 55.425 21.275 ;
        RECT 123.120 21.045 132.705 21.275 ;
        RECT 45.840 21.030 55.415 21.045 ;
        RECT 123.120 21.030 132.695 21.045 ;
      LAYER met2 ;
        RECT 40.045 25.655 43.245 25.690 ;
        RECT 40.045 25.480 43.265 25.655 ;
        RECT 40.045 24.850 43.300 25.480 ;
        RECT 40.045 24.690 43.265 24.850 ;
        RECT 40.045 24.330 43.245 24.690 ;
        RECT 45.900 21.340 46.160 28.585 ;
        RECT 50.480 21.340 50.740 28.585 ;
        RECT 55.060 22.790 55.320 28.585 ;
        RECT 117.365 25.430 117.625 25.480 ;
        RECT 120.320 25.430 120.580 25.480 ;
        RECT 117.365 24.900 120.580 25.430 ;
        RECT 117.365 24.850 117.625 24.900 ;
        RECT 120.320 24.850 120.580 24.900 ;
        RECT 55.060 21.340 62.015 22.790 ;
        RECT 45.900 20.980 62.015 21.340 ;
        RECT 123.180 21.340 123.440 28.585 ;
        RECT 127.760 21.340 128.020 28.585 ;
        RECT 132.340 22.800 132.600 28.585 ;
        RECT 132.340 22.790 138.550 22.800 ;
        RECT 132.340 21.340 139.295 22.790 ;
        RECT 123.180 20.980 139.295 21.340 ;
      LAYER met3 ;
        RECT 60.275 21.245 62.065 22.765 ;
        RECT 137.555 21.245 139.345 22.765 ;
      LAYER met4 ;
        RECT 4.000 53.365 6.000 220.760 ;
        RECT 4.000 51.365 139.965 53.365 ;
        RECT 4.000 5.000 6.000 51.365 ;
        RECT 59.725 21.010 62.685 51.365 ;
        RECT 137.005 21.010 139.965 51.365 ;
    END
  END VGND
  OBS
      LAYER nwell ;
        RECT 38.590 25.830 41.840 28.920 ;
        RECT 115.870 25.830 119.120 28.920 ;
      LAYER li1 ;
        RECT 42.200 42.710 54.785 42.880 ;
        RECT 119.480 42.710 132.065 42.880 ;
        RECT 28.910 38.250 38.910 38.420 ;
        RECT 38.970 37.495 39.140 38.035 ;
        RECT 28.910 37.110 38.910 37.280 ;
        RECT 46.400 37.155 46.570 42.495 ;
        RECT 48.980 37.155 49.150 42.495 ;
        RECT 106.190 38.250 116.190 38.420 ;
        RECT 116.250 37.495 116.420 38.035 ;
        RECT 106.190 37.110 116.190 37.280 ;
        RECT 123.680 37.155 123.850 42.495 ;
        RECT 126.260 37.155 126.430 42.495 ;
        RECT 40.910 36.770 54.785 36.940 ;
        RECT 118.190 36.770 132.065 36.940 ;
        RECT 36.220 36.140 37.220 36.310 ;
        RECT 16.490 31.935 19.340 34.095 ;
        RECT 35.375 33.930 35.545 34.970 ;
        RECT 35.990 33.930 36.160 35.970 ;
        RECT 37.280 33.930 37.450 35.970 ;
        RECT 35.075 33.590 35.405 33.760 ;
        RECT 31.675 32.405 36.665 32.575 ;
        RECT 31.590 27.195 31.760 32.235 ;
        RECT 32.880 27.195 33.050 32.235 ;
        RECT 35.290 27.195 35.460 32.235 ;
        RECT 36.580 27.195 36.750 32.235 ;
        RECT 46.400 31.215 46.570 36.555 ;
        RECT 48.980 31.215 49.150 36.555 ;
        RECT 113.500 36.140 114.500 36.310 ;
        RECT 93.770 31.935 96.620 34.095 ;
        RECT 112.655 33.930 112.825 34.970 ;
        RECT 113.270 33.930 113.440 35.970 ;
        RECT 114.560 33.930 114.730 35.970 ;
        RECT 112.355 33.590 112.685 33.760 ;
        RECT 108.955 32.405 113.945 32.575 ;
        RECT 40.765 30.830 54.785 31.000 ;
        RECT 43.740 28.785 55.190 28.955 ;
        RECT 38.770 28.570 41.660 28.740 ;
        RECT 31.675 26.855 36.665 27.025 ;
        RECT 31.590 21.645 31.760 26.685 ;
        RECT 32.880 21.645 33.050 26.685 ;
        RECT 33.440 21.645 33.610 26.685 ;
        RECT 35.290 21.645 35.460 26.685 ;
        RECT 36.580 21.645 36.750 26.685 ;
        RECT 38.770 26.180 38.940 28.570 ;
        RECT 39.340 26.550 39.510 27.840 ;
        RECT 40.130 26.550 40.300 27.840 ;
        RECT 40.920 26.550 41.090 27.840 ;
        RECT 41.490 26.180 41.660 28.570 ;
        RECT 43.740 27.585 55.190 27.755 ;
        RECT 108.870 27.195 109.040 32.235 ;
        RECT 110.160 27.195 110.330 32.235 ;
        RECT 112.570 27.195 112.740 32.235 ;
        RECT 113.860 27.195 114.030 32.235 ;
        RECT 123.680 31.215 123.850 36.555 ;
        RECT 126.260 31.215 126.430 36.555 ;
        RECT 118.045 30.830 132.065 31.000 ;
        RECT 121.020 28.785 132.470 28.955 ;
        RECT 116.050 28.570 118.940 28.740 ;
        RECT 108.955 26.855 113.945 27.025 ;
        RECT 43.740 26.385 55.190 26.555 ;
        RECT 38.770 26.010 41.660 26.180 ;
        RECT 37.840 24.820 38.010 25.510 ;
        RECT 42.420 24.820 42.590 25.510 ;
        RECT 43.740 25.185 55.190 25.355 ;
        RECT 38.070 24.480 40.070 24.650 ;
        RECT 40.360 24.480 42.360 24.650 ;
        RECT 43.740 23.985 55.190 24.155 ;
        RECT 37.840 23.080 38.010 23.770 ;
        RECT 40.130 23.080 40.300 23.770 ;
        RECT 42.420 23.080 42.590 23.770 ;
        RECT 38.070 22.740 40.070 22.910 ;
        RECT 40.360 22.740 42.360 22.910 ;
        RECT 43.740 22.785 55.190 22.955 ;
        RECT 38.070 22.200 40.070 22.370 ;
        RECT 37.840 21.340 38.010 22.030 ;
        RECT 40.130 21.340 40.300 22.030 ;
        RECT 43.740 21.585 55.190 21.755 ;
        RECT 108.870 21.645 109.040 26.685 ;
        RECT 110.160 21.645 110.330 26.685 ;
        RECT 110.720 21.645 110.890 26.685 ;
        RECT 112.570 21.645 112.740 26.685 ;
        RECT 113.860 21.645 114.030 26.685 ;
        RECT 116.050 26.180 116.220 28.570 ;
        RECT 116.620 26.550 116.790 27.840 ;
        RECT 117.410 26.550 117.580 27.840 ;
        RECT 118.200 26.550 118.370 27.840 ;
        RECT 118.770 26.180 118.940 28.570 ;
        RECT 121.020 27.585 132.470 27.755 ;
        RECT 121.020 26.385 132.470 26.555 ;
        RECT 116.050 26.010 118.940 26.180 ;
        RECT 115.120 24.820 115.290 25.510 ;
        RECT 119.700 24.820 119.870 25.510 ;
        RECT 121.020 25.185 132.470 25.355 ;
        RECT 115.350 24.480 117.350 24.650 ;
        RECT 117.640 24.480 119.640 24.650 ;
        RECT 121.020 23.985 132.470 24.155 ;
        RECT 115.120 23.080 115.290 23.770 ;
        RECT 117.410 23.080 117.580 23.770 ;
        RECT 119.700 23.080 119.870 23.770 ;
        RECT 115.350 22.740 117.350 22.910 ;
        RECT 117.640 22.740 119.640 22.910 ;
        RECT 121.020 22.785 132.470 22.955 ;
        RECT 115.350 22.200 117.350 22.370 ;
        RECT 115.120 21.340 115.290 22.030 ;
        RECT 117.410 21.340 117.580 22.030 ;
        RECT 121.020 21.585 132.470 21.755 ;
        RECT 40.360 21.000 42.360 21.170 ;
        RECT 117.640 21.000 119.640 21.170 ;
      LAYER met1 ;
        RECT 42.220 42.880 54.620 42.910 ;
        RECT 119.500 42.880 131.900 42.910 ;
        RECT 42.220 42.710 54.785 42.880 ;
        RECT 119.500 42.710 132.065 42.880 ;
        RECT 42.220 42.680 54.620 42.710 ;
        RECT 119.500 42.680 131.900 42.710 ;
        RECT 46.370 42.460 46.600 42.475 ;
        RECT 28.930 38.220 39.170 38.450 ;
        RECT 38.940 37.310 39.170 38.220 ;
        RECT 28.930 37.080 39.170 37.310 ;
        RECT 46.305 37.190 46.665 42.460 ;
        RECT 48.885 37.190 49.245 42.680 ;
        RECT 123.650 42.460 123.880 42.475 ;
        RECT 106.210 38.220 116.450 38.450 ;
        RECT 116.220 37.310 116.450 38.220 ;
        RECT 46.370 37.175 46.600 37.190 ;
        RECT 48.950 37.175 49.180 37.190 ;
        RECT 106.210 37.080 116.450 37.310 ;
        RECT 123.585 37.190 123.945 42.460 ;
        RECT 126.165 37.190 126.525 42.680 ;
        RECT 123.650 37.175 123.880 37.190 ;
        RECT 126.230 37.175 126.460 37.190 ;
        RECT 36.240 36.340 37.200 37.080 ;
        RECT 35.345 36.110 37.200 36.340 ;
        RECT 39.405 36.940 54.620 36.970 ;
        RECT 39.405 36.770 54.785 36.940 ;
        RECT 39.405 36.740 54.620 36.770 ;
        RECT 16.510 32.215 19.320 34.035 ;
        RECT 35.345 33.950 35.575 36.110 ;
        RECT 39.405 35.950 39.635 36.740 ;
        RECT 46.370 36.520 46.600 36.535 ;
        RECT 48.950 36.520 49.180 36.535 ;
        RECT 35.895 33.790 36.255 35.950 ;
        RECT 37.250 35.725 39.635 35.950 ;
        RECT 37.250 33.950 37.480 35.725 ;
        RECT 35.055 33.560 36.255 33.790 ;
        RECT 35.945 32.605 36.255 33.560 ;
        RECT 31.840 32.575 36.500 32.605 ;
        RECT 31.675 32.405 36.665 32.575 ;
        RECT 31.840 32.375 36.500 32.405 ;
        RECT 16.510 32.020 31.855 32.215 ;
        RECT 16.510 31.990 19.320 32.020 ;
        RECT 31.495 27.215 31.855 32.020 ;
        RECT 32.785 27.215 33.145 32.215 ;
        RECT 35.195 27.215 35.555 32.215 ;
        RECT 36.485 31.030 36.845 32.215 ;
        RECT 46.305 31.250 46.665 36.520 ;
        RECT 48.885 31.250 49.245 36.520 ;
        RECT 113.520 36.340 114.480 37.080 ;
        RECT 112.625 36.110 114.480 36.340 ;
        RECT 116.685 36.940 131.900 36.970 ;
        RECT 116.685 36.770 132.065 36.940 ;
        RECT 116.685 36.740 131.900 36.770 ;
        RECT 93.790 32.215 96.600 34.035 ;
        RECT 112.625 33.950 112.855 36.110 ;
        RECT 116.685 35.950 116.915 36.740 ;
        RECT 123.650 36.520 123.880 36.535 ;
        RECT 126.230 36.520 126.460 36.535 ;
        RECT 113.175 33.790 113.535 35.950 ;
        RECT 114.530 35.725 116.915 35.950 ;
        RECT 114.530 33.950 114.760 35.725 ;
        RECT 112.335 33.560 113.535 33.790 ;
        RECT 113.225 32.605 113.535 33.560 ;
        RECT 109.120 32.575 113.780 32.605 ;
        RECT 108.955 32.405 113.945 32.575 ;
        RECT 109.120 32.375 113.780 32.405 ;
        RECT 93.790 32.020 109.135 32.215 ;
        RECT 93.790 31.990 96.600 32.020 ;
        RECT 46.370 31.235 46.600 31.250 ;
        RECT 48.950 31.235 49.180 31.250 ;
        RECT 36.485 31.000 54.620 31.030 ;
        RECT 36.485 30.830 54.785 31.000 ;
        RECT 36.485 30.800 54.620 30.830 ;
        RECT 36.485 30.770 40.930 30.800 ;
        RECT 36.485 27.215 36.845 30.770 ;
        RECT 43.905 28.955 55.025 28.985 ;
        RECT 43.740 28.785 55.190 28.955 ;
        RECT 40.035 28.525 40.395 28.785 ;
        RECT 43.905 28.755 55.025 28.785 ;
        RECT 31.840 27.025 36.500 27.055 ;
        RECT 31.675 26.855 36.665 27.025 ;
        RECT 31.840 26.825 36.500 26.855 ;
        RECT 31.495 21.665 31.855 26.665 ;
        RECT 32.785 21.665 33.145 26.665 ;
        RECT 33.410 21.665 33.640 26.825 ;
        RECT 39.310 26.800 39.540 27.820 ;
        RECT 40.100 27.325 40.330 27.820 ;
        RECT 40.035 27.065 40.395 27.325 ;
        RECT 35.195 21.665 35.555 26.665 ;
        RECT 36.485 21.665 36.845 26.665 ;
        RECT 37.810 26.570 39.540 26.800 ;
        RECT 40.100 26.570 40.330 27.065 ;
        RECT 40.890 26.800 41.120 27.820 ;
        RECT 43.905 27.755 55.025 27.785 ;
        RECT 43.740 27.585 55.190 27.755 ;
        RECT 43.905 27.555 55.025 27.585 ;
        RECT 108.775 27.215 109.135 32.020 ;
        RECT 110.065 27.215 110.425 32.215 ;
        RECT 112.475 27.215 112.835 32.215 ;
        RECT 113.765 31.030 114.125 32.215 ;
        RECT 123.585 31.250 123.945 36.520 ;
        RECT 126.165 31.250 126.525 36.520 ;
        RECT 123.650 31.235 123.880 31.250 ;
        RECT 126.230 31.235 126.460 31.250 ;
        RECT 113.765 31.000 131.900 31.030 ;
        RECT 113.765 30.830 132.065 31.000 ;
        RECT 113.765 30.800 131.900 30.830 ;
        RECT 113.765 30.770 118.210 30.800 ;
        RECT 113.765 27.215 114.125 30.770 ;
        RECT 121.185 28.955 132.305 28.985 ;
        RECT 121.020 28.785 132.470 28.955 ;
        RECT 117.315 28.525 117.675 28.785 ;
        RECT 121.185 28.755 132.305 28.785 ;
        RECT 109.120 27.025 113.780 27.055 ;
        RECT 108.955 26.855 113.945 27.025 ;
        RECT 109.120 26.825 113.780 26.855 ;
        RECT 40.890 26.570 42.620 26.800 ;
        RECT 37.810 24.710 38.040 26.570 ;
        RECT 40.035 25.965 40.395 26.225 ;
        RECT 37.810 24.680 39.960 24.710 ;
        RECT 40.440 24.680 42.250 24.710 ;
        RECT 37.810 24.450 42.250 24.680 ;
        RECT 37.810 24.420 39.960 24.450 ;
        RECT 40.440 24.420 42.250 24.450 ;
        RECT 42.390 24.185 42.620 26.570 ;
        RECT 43.905 26.555 55.025 26.585 ;
        RECT 43.740 26.385 55.190 26.555 ;
        RECT 43.905 26.355 55.025 26.385 ;
        RECT 43.905 25.355 55.025 25.385 ;
        RECT 43.740 25.185 55.190 25.355 ;
        RECT 43.905 25.155 55.025 25.185 ;
        RECT 37.810 24.155 55.025 24.185 ;
        RECT 37.810 23.985 55.190 24.155 ;
        RECT 37.810 23.955 55.025 23.985 ;
        RECT 37.810 23.100 38.040 23.955 ;
        RECT 40.100 23.555 40.330 23.750 ;
        RECT 40.035 23.295 40.395 23.555 ;
        RECT 40.100 23.100 40.330 23.295 ;
        RECT 42.390 23.100 42.620 23.955 ;
        RECT 43.905 22.955 55.025 22.985 ;
        RECT 38.090 22.710 42.340 22.940 ;
        RECT 43.740 22.785 55.190 22.955 ;
        RECT 43.905 22.755 55.025 22.785 ;
        RECT 38.090 22.400 40.050 22.710 ;
        RECT 37.810 22.170 40.050 22.400 ;
        RECT 37.810 22.155 38.510 22.170 ;
        RECT 38.890 22.155 39.250 22.170 ;
        RECT 39.630 22.155 39.990 22.170 ;
        RECT 37.810 21.815 38.040 22.155 ;
        RECT 37.745 21.555 38.105 21.815 ;
        RECT 37.810 21.360 38.040 21.555 ;
        RECT 40.100 21.200 40.330 22.010 ;
        RECT 43.905 21.755 55.025 21.785 ;
        RECT 43.740 21.585 55.190 21.755 ;
        RECT 108.775 21.665 109.135 26.665 ;
        RECT 110.065 21.665 110.425 26.665 ;
        RECT 110.690 21.665 110.920 26.825 ;
        RECT 116.590 26.800 116.820 27.820 ;
        RECT 117.380 27.325 117.610 27.820 ;
        RECT 117.315 27.065 117.675 27.325 ;
        RECT 112.475 21.665 112.835 26.665 ;
        RECT 113.765 21.665 114.125 26.665 ;
        RECT 115.090 26.570 116.820 26.800 ;
        RECT 117.380 26.570 117.610 27.065 ;
        RECT 118.170 26.800 118.400 27.820 ;
        RECT 121.185 27.755 132.305 27.785 ;
        RECT 121.020 27.585 132.470 27.755 ;
        RECT 121.185 27.555 132.305 27.585 ;
        RECT 118.170 26.570 119.900 26.800 ;
        RECT 115.090 24.710 115.320 26.570 ;
        RECT 117.315 25.965 117.675 26.225 ;
        RECT 115.090 24.680 117.240 24.710 ;
        RECT 117.720 24.680 119.530 24.710 ;
        RECT 115.090 24.450 119.530 24.680 ;
        RECT 115.090 24.420 117.240 24.450 ;
        RECT 117.720 24.420 119.530 24.450 ;
        RECT 119.670 24.185 119.900 26.570 ;
        RECT 121.185 26.555 132.305 26.585 ;
        RECT 121.020 26.385 132.470 26.555 ;
        RECT 121.185 26.355 132.305 26.385 ;
        RECT 121.185 25.355 132.305 25.385 ;
        RECT 121.020 25.185 132.470 25.355 ;
        RECT 121.185 25.155 132.305 25.185 ;
        RECT 115.090 24.155 132.305 24.185 ;
        RECT 115.090 23.985 132.470 24.155 ;
        RECT 115.090 23.955 132.305 23.985 ;
        RECT 115.090 23.100 115.320 23.955 ;
        RECT 117.380 23.555 117.610 23.750 ;
        RECT 117.315 23.295 117.675 23.555 ;
        RECT 117.380 23.100 117.610 23.295 ;
        RECT 119.670 23.100 119.900 23.955 ;
        RECT 121.185 22.955 132.305 22.985 ;
        RECT 115.370 22.710 119.620 22.940 ;
        RECT 121.020 22.785 132.470 22.955 ;
        RECT 121.185 22.755 132.305 22.785 ;
        RECT 115.370 22.400 117.330 22.710 ;
        RECT 115.090 22.170 117.330 22.400 ;
        RECT 115.090 22.155 115.790 22.170 ;
        RECT 116.170 22.155 116.530 22.170 ;
        RECT 116.910 22.155 117.270 22.170 ;
        RECT 115.090 21.815 115.320 22.155 ;
        RECT 43.905 21.555 55.025 21.585 ;
        RECT 115.025 21.555 115.385 21.815 ;
        RECT 115.090 21.360 115.320 21.555 ;
        RECT 117.380 21.200 117.610 22.010 ;
        RECT 121.185 21.755 132.305 21.785 ;
        RECT 121.020 21.585 132.470 21.755 ;
        RECT 121.185 21.555 132.305 21.585 ;
        RECT 40.100 20.970 42.340 21.200 ;
        RECT 117.380 20.970 119.620 21.200 ;
      LAYER met2 ;
        RECT 46.355 40.020 46.615 42.510 ;
        RECT 46.345 39.640 46.625 40.020 ;
        RECT 46.355 37.160 46.615 39.640 ;
        RECT 48.935 37.160 49.195 42.510 ;
        RECT 123.635 40.020 123.895 42.510 ;
        RECT 123.625 39.640 123.905 40.020 ;
        RECT 123.635 37.160 123.895 39.640 ;
        RECT 126.215 37.160 126.475 42.510 ;
        RECT 35.945 33.090 36.205 36.000 ;
        RECT 31.545 32.455 35.505 32.715 ;
        RECT 35.935 32.710 36.215 33.090 ;
        RECT 46.355 32.800 46.615 36.550 ;
        RECT 48.935 35.445 49.195 36.550 ;
        RECT 48.925 35.065 49.205 35.445 ;
        RECT 31.545 21.615 31.805 32.455 ;
        RECT 32.835 21.475 33.095 32.265 ;
        RECT 35.245 21.615 35.505 32.455 ;
        RECT 46.345 32.420 46.625 32.800 ;
        RECT 36.535 21.475 36.795 32.265 ;
        RECT 46.355 31.200 46.615 32.420 ;
        RECT 48.935 31.200 49.195 35.065 ;
        RECT 113.225 33.090 113.485 36.000 ;
        RECT 108.825 32.455 112.785 32.715 ;
        RECT 113.215 32.710 113.495 33.090 ;
        RECT 123.635 32.800 123.895 36.550 ;
        RECT 126.215 35.445 126.475 36.550 ;
        RECT 126.205 35.065 126.485 35.445 ;
        RECT 40.075 29.455 40.355 29.835 ;
        RECT 40.085 25.915 40.345 29.455 ;
        RECT 40.075 23.235 40.355 23.615 ;
        RECT 37.785 21.495 38.065 21.875 ;
        RECT 108.825 21.615 109.085 32.455 ;
        RECT 32.835 21.215 36.795 21.475 ;
        RECT 110.115 21.475 110.375 32.265 ;
        RECT 112.525 21.615 112.785 32.455 ;
        RECT 123.625 32.420 123.905 32.800 ;
        RECT 113.815 21.475 114.075 32.265 ;
        RECT 123.635 31.200 123.895 32.420 ;
        RECT 126.215 31.200 126.475 35.065 ;
        RECT 117.355 29.455 117.635 29.835 ;
        RECT 117.365 25.915 117.625 29.455 ;
        RECT 117.355 23.235 117.635 23.615 ;
        RECT 115.065 21.495 115.345 21.875 ;
        RECT 110.115 21.215 114.075 21.475 ;
      LAYER met3 ;
        RECT 35.885 39.665 46.675 39.995 ;
        RECT 113.165 39.665 123.955 39.995 ;
        RECT 35.885 32.735 36.265 39.665 ;
        RECT 37.735 35.090 49.255 35.420 ;
        RECT 37.735 21.520 38.115 35.090 ;
        RECT 40.025 32.445 46.675 32.775 ;
        RECT 113.165 32.735 113.545 39.665 ;
        RECT 115.015 35.090 126.535 35.420 ;
        RECT 40.025 29.480 40.405 32.445 ;
        RECT 40.025 20.570 40.405 23.590 ;
        RECT 115.015 21.520 115.395 35.090 ;
        RECT 117.305 32.445 123.955 32.775 ;
        RECT 117.305 29.480 117.685 32.445 ;
        RECT 117.305 20.570 117.685 23.590 ;
        RECT 39.160 9.670 51.820 20.570 ;
        RECT 116.440 9.670 129.100 20.570 ;
      LAYER met4 ;
        RECT 51.320 9.730 51.800 20.510 ;
        RECT 128.600 9.730 129.080 20.510 ;
  END
END tt_um_analog_ota_v3
END LIBRARY

